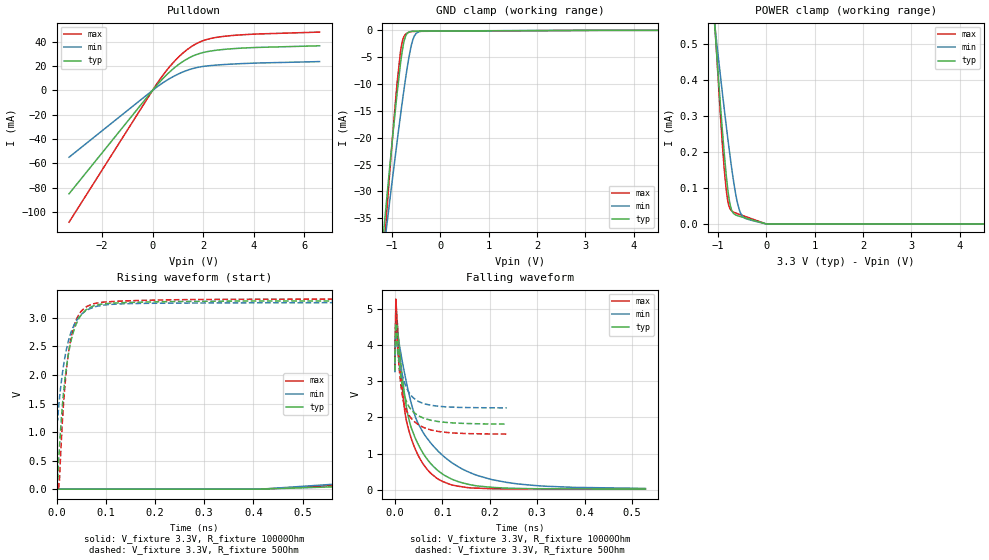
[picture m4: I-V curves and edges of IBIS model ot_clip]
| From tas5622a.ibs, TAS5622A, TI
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|   ot_clip Model
[Model]   ot_clip
Model_type   Open_drain
Polarity   Inverting
Vmeas = 1.65
Vref = 3.3
Cref = 2pF
Rref = 10000
|   typ   min   max
|   (nom PVT)   (fast PVT)   (slow PVT)
 C_comp   8.114e-13   8.085e-13   8.261e-13
|ON state : BUFFER OUTPUT TURNED LOW
|C_comp   8.114e-13   8.085e-13   8.261e-13
|OFF state: BUFFER IN HIGH IMPEDANCE
|C_comp   3.252e-13   2.757e-13   3.645e-13
| Where nom  PVT is Nominal Process, 3.3V, 27C
|   Fast PVT is Strong Process,  3.33V, 0C
|   Slow PVT is Weak Process,   3.27V, 125C
[Voltage Range]   3.3   3.27   3.33
|Ambient Temperature   25   70   0
|Junction Temperature
[Temperature Range]   27   125   0
[Pullup Reference]   3.3   3.27   3.33
[Pulldown Reference]   0   0   0
[Power Clamp Reference]   3.3   3.27   3.33
[GND Clamp Reference]   0   0   0
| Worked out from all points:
|   slope of the pulldown table from 0 to 0.495 V, typ, clamps not added: 42.9 ohm
|   GND clamp passes 1 mA (typ) near -0.72 V on its own axis
|   POWER clamp passes 1 mA (typ) near -1.29 V on its own axis
|   falling waveform, V_fixture 3.3V, R_fixture 10000Ohm: 20-80 % time 58.6ps typ, 97.6ps min, 44.8ps max; typ from 3.3 V to 0.019 V
|   rising waveform, V_fixture 3.3V, R_fixture 10000Ohm: 20-80 % time 4.38ns typ, 5.36ns min, 3.46ns max; typ from 0.018 V to 3.3 V
|   falling waveform, V_fixture 3.3V, R_fixture 50Ohm: 20-80 % time 28.7ps typ, 28.8ps min, 28.1ps max; typ from 3.3 V to 1.81 V
|   rising waveform, V_fixture 3.3V, R_fixture 50Ohm: 20-80 % time 26.6ps typ, 30.7ps min, 22.4ps max; typ from 1.8 V to 3.3 V
[Pulldown]
|   Voltage   I(typ)   I(min)   I(max)
-3.3V     -85.03mA   -54.97mA   -108.4mA
202.2mV   5.008mA    3.215mA    6.411mA
584.8mV   13.4mA     8.582mA    17.2mA
867.9mV   18.66mA    11.93mA    24.02mA
1.15V     23.07mA    14.72mA    29.81mA
1.432V    26.62mA    16.95mA    34.54mA
1.713V    29.29mA    18.6mA     38.22mA
1.995V    31.12mA    19.69mA    40.86mA
2.7V      33.45mA    21.07mA    44.13mA
3.969V    35.2mA     22.38mA    46.22mA
6.6V      36.67mA    23.68mA    47.95mA
[GND Clamp]
|   Voltage   I(typ)   I(min)   I(max)
-3.3V     -216.1mA   -188.1mA   -249.4mA
-1.802V   -97.82mA   -88.04mA   -116.6mA
-1.046V   -25.32mA   -31.7mA    -26.32mA
-914.1mV  -13.35mA   -22.1mA    -11.71mA
-825mV    -6.232mA   -15.85mA   -3.985mA
-785.9mV  -3.709mA   -13.2mA    -2.004mA
-745.8mV  -1.834mA   -10.59mA   -1.033mA
-646.8mV  -316.4uA   -4.856mA   -343uA
-594mV    -189.8uA   -2.549mA   -241.8uA
-542.8mV  -155.5uA   -1.13mA    -202.7uA
-402.6mV  -142.5uA   -180.1uA   -180uA
6.6V      0A         0A         0A
[POWER Clamp]
|   Voltage   I(typ)   I(min)   I(max)
-3.3V     5.287mA    3.463mA    6.313mA
-1.129V   677.4uA    632.8uA    715.7uA
-1.043V   509.2uA    527.2uA    513.6uA
-917.4mV  278.2uA    377.1uA    242.4uA
-825mV    133.2uA    271.4uA    92.66uA
-749.2mV  55.36uA    190.1uA    42.61uA
-697.1mV  33.33uA    138.8uA    34.64uA
-619.3mV  24.38uA    74.48uA    29.88uA
-542.8mV  20.92uA    34.29uA    26.13uA
-474.7mV  18.27uA    19.38uA    22.85uA
-570uV    21.98nA    19.14nA    93.78nA
6.6V      0A         0A         0A
[Ramp]
R_load = 10000
|   typ   min   max
dV/dt_r   1.96936/4.37648e-09   1.9462/5.36187e-09   1.98902/3.46597e-09
dV/dt_f   1.96937/5.86647e-11   1.94632/9.83471e-11   1.98902/4.47642e-11
[Falling Waveform]
V_fixture = 3.3V
V_fixture_min = 3.27V
V_fixture_max = 3.33V
R_fixture = 10000Ohm
|   Time   V(typ)   V(min)   V(max)
0s        3.3V       3.27V      3.33V
2ps       4.92V      4.658V     5.278V
16ps      3.097V     3.524V     2.742V
22ps      2.481V     3.118V     2.075V
28ps      2.035V     2.748V     1.71V
50ps      1.232V     1.806V     926.4mV
100ps     437mV      956.3mV    231.9mV
162ps     129.1mV    452.4mV    47.82mV
236ps     43.43mV    201.3mV    23.48mV
528ps     18.59mV    35.72mV    14.58mV
[Rising Waveform]
V_fixture = 3.3V
V_fixture_min = 3.27V
V_fixture_max = 3.33V
R_fixture = 10000Ohm
|   Time   V(typ)   V(min)   V(max)
0s        17.72mV    26.13mV    14.97mV
414ps     0V         0V         0V
734ps     87.35mV    184.8mV    138.9mV
2.062ns   1.126V     1.013V     1.414V
3.546ns   1.941V     1.726V     2.277V
5.184ns   2.497V     2.266V     2.785V
7.596ns   2.926V     2.736V     3.119V
11.14ns   3.175V     3.054V     3.276V
16.02ns   3.272V     3.205V     3.321V
40ns      3.3V       3.27V      3.33V
[Falling Waveform]
V_fixture = 3.3V
V_fixture_min = 3.27V
V_fixture_max = 3.33V
R_fixture = 50Ohm
|   Time   V(typ)   V(min)   V(max)
0s        3.3V       3.27V      3.33V
2ps       4.605V     4.361V     4.918V
4ps       4.209V     4.102V     4.374V
8ps       3.608V     3.699V     3.547V
14ps      2.998V     3.269V     2.749V
22ps      2.529V     2.903V     2.269V
36ps      2.189V     2.582V     1.952V
60ps      1.985V     2.388V     1.727V
92ps      1.886V     2.311V     1.612V
236ps     1.815V     2.266V     1.54V
[Rising Waveform]
V_fixture = 3.3V
V_fixture_min = 3.27V
V_fixture_max = 3.33V
R_fixture = 50Ohm
|   Time   V(typ)   V(min)   V(max)
0s        1.804V     2.256V     1.534V
2ps       138.6mV    1.204V     0V
6ps       738.8mV    1.59V      152.7mV
14ps      1.666V     2.152V     1.466V
20ps      2.128V     2.443V     2.079V
26ps      2.453V     2.653V     2.48V
40ps      2.892V     2.945V     2.965V
62ps      3.153V     3.138V     3.202V
180ps     3.278V     3.255V     3.308V
780ps     3.299V     3.268V     3.33V
